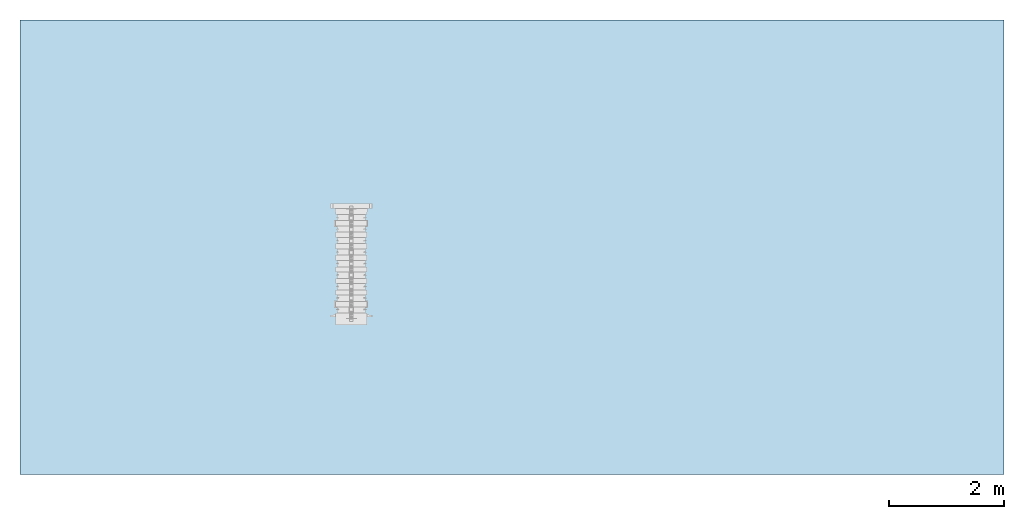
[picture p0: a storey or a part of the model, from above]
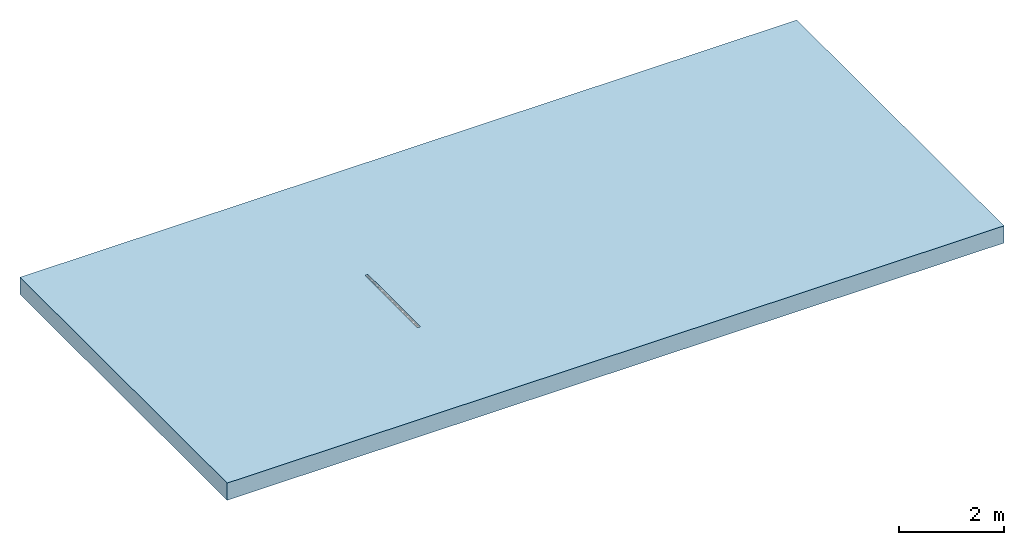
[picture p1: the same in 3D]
Properties of the parts of a building model (IFC2X3)

# File
Description: ViewDefinition [CoordinationView]
File name: 32831 - Q-Guard Edge - D.I.ifc
Time: 2013-07-11T16:54:45
Written by: Autodesk Revit 2013
Made in: 20120221_2030(x64)

# IfcProject, Project Number
LongName: Project Name; Phase: Project Status

# IfcSite, Default
RefLatitude: 42, 21, 30, 344238; RefLongitude: -71, -3, -35, -194702; RefElevation: 0 mm

# IfcBuilding
Pset_BuildingCommon - NumberOfStoreys: 1
Other - Project Issue Date: Issue Date; Client Name: Owner; Project Address: ## Street City, State Zip; Project Name: Project Name; Project Number: Project Number; Project Status: Project Status

# IfcBuildingStorey, Level 1
LongName: Level 1; Elevation: 0 mm
Constraints - Elevation Base: 0; Elevation: 0 mm
Graphics - Symbol at End 1 Default: no; Line Pattern: Center; Line Weight: 1; Symbol: M_Level Head - Circle: M_Level Head - Circle; Color: 0; Symbol at End 2 Default: yes
Identity Data - Name: Level 1; Building Story: yes; Structural: no
Dimensions - Computation Height: 0 mm

# IfcFlowTerminal: 32831 - Q-Guard Edge - D.I, Qmax 700:32831 - Q-Guard Edge - D.I:32831 - Q-Guard Edge - D.I:502881
In: Level 1
Construction - 32854_Chamber connector (at Female end): no; 32854_Chamber connector (at Male end): no; 32835_Closing End cap (at Female end): no; 32835_Closing End cap (at Male end): yes; 32882_550-700 Step Connector: no; E2-QGuard-DuctileIron: yes; V_Coarse_E5: no; E3-QFlow-GalvSteel: no; E4-QGuard-GalvSteel: no; E5-QSlot-GalvSteel: no; E1-QFlow-DuctileIron: no; V_CoarseE1: yes
Identity Data - Mark: 37; Fax: +44 (0)1462 815895; Assembly Description: Rain Water Drainage; Model Description: High capacity slot drainage channel system; Manufacturer: ACO Technologies plc - ACO Water Management Division; e-mail Sales: customersupport@aco.co.uk; Assembly Code: D2040; Product Code: 32831; Telephone: +44 (0)1462 816666; e-mail Technical: technical@aco.co.uk; Address: ACO Business Park, Hitchin Road, Shefford, Bedfordshire, United Kingdom SG17 5TE; Price: POA - contact ACO; Cost: 0; Product Brochure: http://www.aco.co.uk/download.php?id=220; Installation Guidelines: http://www.aco.co.uk/download.php?id=220; Type Comments: ACO Qmax 700 channel assembly complete with ACO Q-Guard ductile iron edge rail; Model: ACO Qmax 700; URL: www.aco.co.uk; OmniClass Number: 23.70.50.24; Maintenance Guidelines: http://www.aco.co.uk/download.php?id=220; Product Page URL: http://www.aco.co.uk/product_detail.php?id=79; OmniClass Title: Rainwater Removal
Phasing - Phase Created: New Construction
Constraints - Moves With Nearby Elements: no; Level: Level: Level 1
Model Properties - Closing End Cap Model Description: High capacity slot drainage channel system; Closing End Cap Weight: 4.9 kg; Closing End Cap Product Code: 32835; 550-700 Step Connector Model Description: High capacity slot drainage channel system; 550-700 Step Connector Recyclable: Fully recyclable; 550-700 Step Connector Dimensions: 730mm x 45mm x 865mm (LxWxH); Chamber Connector Channel Material: Medium Density Polyethylene; 550-700 Step Connector Colour: Black; Chamber Connector Recycled Material Content: Variable %; 550-700 Step Connector Material: High Density Polyethylene; Closing End Cap Dimensions: 730mm x 12mm x 865mm (LxWxH); 550-700 Step Connector Recycled Material Content: 0%; Closing End Cap Recycled Material Content: 0%; Chamber Connector Channel Colour: Black; Chamber Connector Recyclable: Fully recyclable; Closing End Cap Recyclable: Fully recyclable; Chamber Connector Model Description: High capacity slot drainage channel system; Chamber Connector Weight: 15.8 kg; Chamber Connector Product Code: 32854; Closing End Cap Colour: Black; 550-700 Step Connector Weight: 2.5 kg; Closing End Cap Material: High Density Polyethylene; 550-700 Step Connector Product Code: 32882; Chamber Connector Dimensions: Female End=800mm x 715mm x 895mm, Male End=800mm x 715mm x 845mm (LxWxH)
Green Building Properties - Channel Recyclable: Fully recyclable; Seal Recycled Material Content: 0%; Seal Recyclable: Fully recyclable; Edge Rail Recyclable: Fully recyclable; Edge Rail Recycled Material Content: Between 40% - 90%; Channel Recycled Material Content: Variable %
Dimensions - Floor Opening Width: 65 mm; ClosingEndCapOrigin: 570.2 mm; ChamberOrigin: 480 mm; Depth Overall: 1070 mm; Length: 2000 mm; StepConn-Origin: 580.3 mm; Width Overall: 730 mm
Data - Product Dimensions: 2000mm x 730mm x 1070mm (LxWxH); Hydraulic Performance: http://www.aco.co.uk/download.php?id=220 http://www.acodesign.co.uk; Load Class: A 15 - F 900; Installation - Concrete Grade: Refer to brochure; Drainage Slot Width: 8mm twin slot; Invert Depth: 950mm; Product Weight: 50.7 kg; Installation - Reinforcement Details: Refer to brochure; Channel C.S.A: 249703mm²; ACO Hydraulic Design Software: http://www.acodesign.co.uk; Concrete Surround Volume - Load Class E 600 - F 900: 0.72 m³/m; Product Standard: BS EN 1433:2002 CE marked; Drainage Slot Intake Area: 10925mm²/m; Concrete Surround Volume - Load Class A 15 - D 400: 0.56 m³/m
General - TagNumber: 0; SerialNumber: 0
Materials and Finishes - Edge Rail Finish: ATec coating; Seal Colour: Black; Edge Rail Material: Ductile Iron; Edge Rail Colour: Black; Seal Material: EPDM; Channel Colour: Black; Channel Material: Medium Density Polyethylene
Other - Revision: 1; Created by: www.aco.co.uk

# IfcOpeningElement: Opening
In: Level 1
Constraints - Level: Level: Level 1; Height Offset From Level: 0 mm; Room Bounding: yes; Related to Mass: no
Structural - Structural: no; Enable Analytical Model: no
Dimensions - Area: 134960000 mm2; Perimeter: 50000 mm; Volume: 53480000000 mm3; Thickness: 400 mm
Phasing - Phase Created: New Construction
Analytical Properties - Roughness: 1; Absorptance: 0.1
Graphics - Coarse Scale Fill Color: 0
Construction - Function: 0; Default Thickness: 400 mm
Materials and Finishes - Structural Material: Plant

# IfcSlab: Floor:Generic Floor - 400mm, Floor:Generic Floor - 400mm:193825
In: Level 1
PredefinedType: FLOOR; Material: Plant 400 mm
Constraints - Level: Level: Level 1; Height Offset From Level: 0 mm; Room Bounding: yes; Related to Mass: no
Structural - Structural: no; Enable Analytical Model: no
Dimensions - Area: 134960000 mm2; Perimeter: 50000 mm; Volume: 53480000000 mm3; Thickness: 400 mm
Phasing - Phase Created: New Construction
Pset_SlabCommon - Reference: Generic Floor - 400mm; IsExternal: no; LoadBearing: yes
Analytical Properties - Roughness: 1; Absorptance: 0.1
Graphics - Coarse Scale Fill Color: 0
Construction - Function: 0; Default Thickness: 400 mm
Materials and Finishes - Structural Material: Plant
